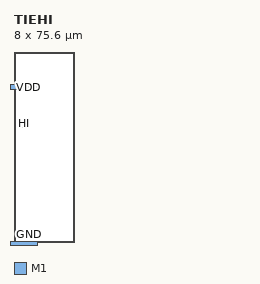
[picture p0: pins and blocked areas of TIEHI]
MACRO TIEHI
  CLASS CORE ;
  SITE TR1um_access_site ;
  ORIGIN 0 0 ;
  SIZE 8.000 BY 75.600 ;
  PIN HI
    DIRECTION OUTPUT ;
    USE SIGNAL ;
    PORT
      LAYER M1 ;
        RECT 2.500 45.500 5.500 48.500 ;
    END
  END HI
  PIN VDD
    DIRECTION INOUT ;
    USE POWER ;
    PORT
      LAYER M1 ;
        RECT -1.300 60.600 9.300 62.600 ;
    END
  END VDD
  PIN GND
    DIRECTION INOUT ;
    USE GROUND ;
    PORT
      LAYER M1 ;
        RECT -1.300 -1.300 9.300 0.300 ;
    END
  END GND
END TIEHI
